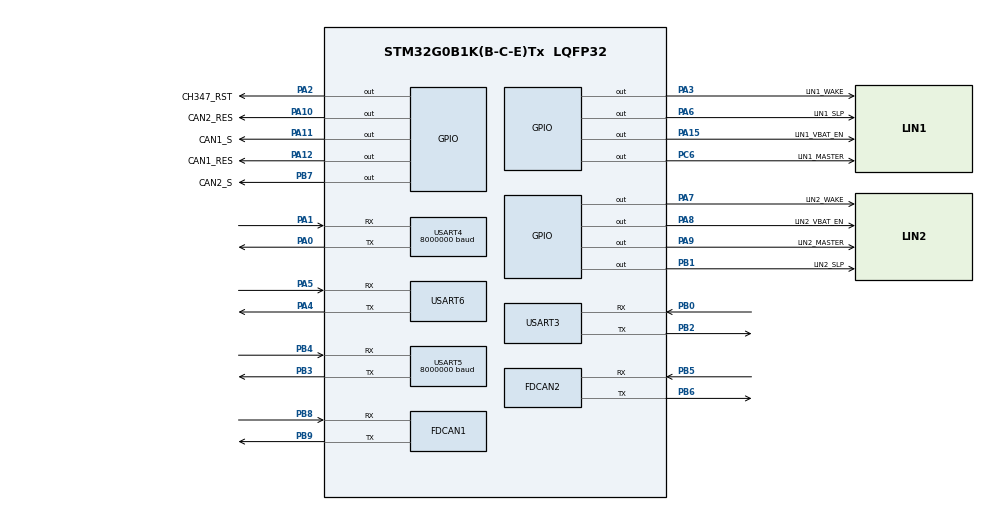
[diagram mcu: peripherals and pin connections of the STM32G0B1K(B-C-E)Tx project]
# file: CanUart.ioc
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Dma.Request0=USART4_RX
Dma.Request1=USART4_TX
Dma.Request2=USART5_RX
Dma.Request3=USART5_TX
Dma.USART4_RX.0.Direction=DMA_PERIPH_TO_MEMORY
Dma.USART4_RX.0.EventEnable=DISABLE
Dma.USART4_RX.0.Instance=DMA1_Channel2
Dma.USART4_RX.0.MemDataAlignment=DMA_MDATAALIGN_BYTE
Dma.USART4_RX.0.MemInc=DMA_MINC_ENABLE
Dma.USART4_RX.0.Mode=DMA_NORMAL
Dma.USART4_RX.0.PeriphDataAlignment=DMA_PDATAALIGN_BYTE
Dma.USART4_RX.0.PeriphInc=DMA_PINC_DISABLE
Dma.USART4_RX.0.Polarity=HAL_DMAMUX_REQ_GEN_RISING
Dma.USART4_RX.0.Priority=DMA_PRIORITY_LOW
Dma.USART4_RX.0.RequestNumber=1
Dma.USART4_RX.0.SignalID=NONE
Dma.USART4_RX.0.SyncEnable=DISABLE
Dma.USART4_RX.0.SyncPolarity=HAL_DMAMUX_SYNC_NO_EVENT
Dma.USART4_RX.0.SyncRequestNumber=1
Dma.USART4_RX.0.SyncSignalID=NONE
Dma.USART4_TX.1.Direction=DMA_MEMORY_TO_PERIPH
Dma.USART4_TX.1.EventEnable=DISABLE
Dma.USART4_TX.1.Instance=DMA1_Channel1
Dma.USART4_TX.1.MemDataAlignment=DMA_MDATAALIGN_BYTE
Dma.USART4_TX.1.MemInc=DMA_MINC_ENABLE
Dma.USART4_TX.1.Mode=DMA_NORMAL
Dma.USART4_TX.1.PeriphDataAlignment=DMA_PDATAALIGN_BYTE
Dma.USART4_TX.1.PeriphInc=DMA_PINC_DISABLE
Dma.USART4_TX.1.Polarity=HAL_DMAMUX_REQ_GEN_RISING
Dma.USART4_TX.1.Priority=DMA_PRIORITY_LOW
Dma.USART4_TX.1.RequestNumber=1
Dma.USART4_TX.1.SignalID=NONE
Dma.USART4_TX.1.SyncEnable=DISABLE
Dma.USART4_TX.1.SyncPolarity=HAL_DMAMUX_SYNC_NO_EVENT
Dma.USART4_TX.1.SyncRequestNumber=1
Dma.USART4_TX.1.SyncSignalID=NONE
Dma.USART5_RX.2.Direction=DMA_PERIPH_TO_MEMORY
Dma.USART5_RX.2.EventEnable=DISABLE
Dma.USART5_RX.2.Instance=DMA1_Channel3
Dma.USART5_RX.2.MemDataAlignment=DMA_MDATAALIGN_BYTE
Dma.USART5_RX.2.MemInc=DMA_MINC_ENABLE
Dma.USART5_RX.2.Mode=DMA_NORMAL
Dma.USART5_RX.2.PeriphDataAlignment=DMA_PDATAALIGN_BYTE
Dma.USART5_RX.2.PeriphInc=DMA_PINC_DISABLE
Dma.USART5_RX.2.Polarity=HAL_DMAMUX_REQ_GEN_RISING
Dma.USART5_RX.2.Priority=DMA_PRIORITY_LOW
Dma.USART5_RX.2.RequestNumber=1
Dma.USART5_RX.2.SignalID=NONE
Dma.USART5_RX.2.SyncEnable=DISABLE
Dma.USART5_RX.2.SyncPolarity=HAL_DMAMUX_SYNC_NO_EVENT
Dma.USART5_RX.2.SyncRequestNumber=1
Dma.USART5_RX.2.SyncSignalID=NONE
Dma.USART5_TX.3.Direction=DMA_MEMORY_TO_PERIPH
Dma.USART5_TX.3.EventEnable=DISABLE
Dma.USART5_TX.3.Instance=DMA1_Channel4
Dma.USART5_TX.3.MemDataAlignment=DMA_MDATAALIGN_BYTE
Dma.USART5_TX.3.MemInc=DMA_MINC_ENABLE
Dma.USART5_TX.3.Mode=DMA_NORMAL
Dma.USART5_TX.3.PeriphDataAlignment=DMA_PDATAALIGN_BYTE
Dma.USART5_TX.3.PeriphInc=DMA_PINC_DISABLE
Dma.USART5_TX.3.Polarity=HAL_DMAMUX_REQ_GEN_RISING
Dma.USART5_TX.3.Priority=DMA_PRIORITY_LOW
Dma.USART5_TX.3.RequestNumber=1
Dma.USART5_TX.3.SignalID=NONE
Dma.USART5_TX.3.SyncEnable=DISABLE
Dma.USART5_TX.3.SyncPolarity=HAL_DMAMUX_SYNC_NO_EVENT
Dma.USART5_TX.3.SyncRequestNumber=1
Dma.USART5_TX.3.SyncSignalID=NONE
FDCAN1.CalculateBaudRateNominal=1000000
FDCAN1.CalculateTimeBitNominal=1000
FDCAN1.CalculateTimeQuantumNominal=125.0
FDCAN1.DataPrescaler=2
FDCAN1.DataTimeSeg1=6
FDCAN1.FrameFormat=FDCAN_FRAME_FD_BRS
FDCAN1.NominalPrescaler=8
FDCAN1.NominalTimeSeg1=5
FDCAN2.CalculateBaudRateNominal=1000000
FDCAN2.CalculateTimeBitNominal=1000
FDCAN2.CalculateTimeQuantumNominal=125.0
FDCAN2.DataPrescaler=2
FDCAN2.DataTimeSeg1=6
FDCAN2.FrameFormat=FDCAN_FRAME_FD_BRS
FDCAN2.NominalPrescaler=8
FDCAN2.NominalTimeSeg1=5
Mcu.Family=STM32G0
Mcu.Name=STM32G0B1K(B-C-E)Tx
Mcu.Package=LQFP32
NVIC.DMA1_Ch4_7_DMA2_Ch1_5_DMAMUX1_OVR_IRQn=true\:0\:0\:false\:false\:true\:false\:true\:true
NVIC.DMA1_Channel1_IRQn=true\:0\:0\:false\:false\:true\:false\:true\:true
NVIC.DMA1_Channel2_3_IRQn=true\:0\:0\:false\:false\:true\:false\:true\:true
NVIC.TIM16_FDCAN_IT0_IRQn=true\:0\:0\:false\:false\:true\:true\:true\:true
NVIC.TIM17_FDCAN_IT1_IRQn=true\:0\:0\:false\:false\:true\:true\:true\:true
NVIC.USART3_4_5_6_LPUART1_IRQn=true\:0\:0\:false\:false\:true\:true\:true\:true
PA0.GPIO_Speed=GPIO_SPEED_FREQ_VERY_HIGH
PA0.Mode=Asynchronous
PA0.Signal=USART4_TX
PA1.GPIO_Speed=GPIO_SPEED_FREQ_VERY_HIGH
PA1.Mode=Asynchronous
PA1.Signal=USART4_RX
PA10.GPIO_Label=CAN2_RES
PA10.Signal=GPIO_Output
PA11\ [PA9].GPIO_Label=CAN1_S
PA11\ [PA9].Signal=GPIO_Output
PA12\ [PA10].GPIO_Label=CAN1_RES
PA12\ [PA10].Signal=GPIO_Output
PA13.Mode=Serial_Wire
PA13.Signal=SYS_SWDIO
PA14-BOOT0.Mode=Serial_Wire
PA14-BOOT0.Signal=SYS_SWCLK
PA15.GPIO_Label=LIN1_VBAT_EN
PA15.Signal=GPIO_Output
PA2.GPIO_Label=CH347_RST
PA2.Signal=GPIO_Output
PA3.GPIO_Label=LIN1_WAKE
PA3.Signal=GPIO_Output
PA4.GPIO_Speed=GPIO_SPEED_FREQ_VERY_HIGH
PA4.Mode=Asynchronous
PA4.Signal=USART6_TX
PA5.GPIO_Speed=GPIO_SPEED_FREQ_VERY_HIGH
PA5.Mode=Asynchronous
PA5.Signal=USART6_RX
PA6.GPIO_Label=LIN1_SLP
PA6.Signal=GPIO_Output
PA7.GPIO_Label=LIN2_WAKE
PA7.Signal=GPIO_Output
PA8.GPIO_Label=LIN2_VBAT_EN
PA8.Signal=GPIO_Output
PA9.GPIO_Label=LIN2_MASTER
PA9.Signal=GPIO_Output
PB0.GPIO_Speed=GPIO_SPEED_FREQ_VERY_HIGH
PB0.Mode=LIN
PB0.Signal=USART3_RX
PB1.GPIO_Label=LIN2_SLP
PB1.Signal=GPIO_Output
PB2.GPIO_Speed=GPIO_SPEED_FREQ_VERY_HIGH
PB2.Mode=LIN
PB2.Signal=USART3_TX
PB3.GPIO_Speed=GPIO_SPEED_FREQ_VERY_HIGH
PB3.Mode=Asynchronous
PB3.Signal=USART5_TX
PB4.GPIO_Speed=GPIO_SPEED_FREQ_VERY_HIGH
PB4.Mode=Asynchronous
PB4.Signal=USART5_RX
PB5.GPIO_Speed=GPIO_SPEED_FREQ_VERY_HIGH
PB5.Mode=FDCAN_Activate
PB5.Signal=FDCAN2_RX
PB6.GPIO_Speed=GPIO_SPEED_FREQ_VERY_HIGH
PB6.Mode=FDCAN_Activate
PB6.Signal=FDCAN2_TX
PB7.GPIO_Label=CAN2_S
PB7.Signal=GPIO_Output
PB8.GPIO_Speed=GPIO_SPEED_FREQ_VERY_HIGH
PB8.Mode=FDCAN_Activate
PB8.Signal=FDCAN1_RX
PB9.GPIO_Speed=GPIO_SPEED_FREQ_VERY_HIGH
PB9.Mode=FDCAN_Activate
PB9.Signal=FDCAN1_TX
PC14-OSC32_IN\ (PC14).Mode=HSE-External-Clock-Source
PC14-OSC32_IN\ (PC14).Signal=RCC_OSC_IN
PC15-OSC32_OUT\ (PC15).Mode=OSC enable
PC15-OSC32_OUT\ (PC15).Signal=RCC_OSC_EN
PC6.GPIO_Label=LIN1_MASTER
PC6.Signal=GPIO_Output
ProjectManager.HeapSize=0x200
ProjectManager.StackSize=0x400
ProjectManager.TargetToolchain=Makefile
RCC.ADCFreq_Value=64000000
RCC.AHBFreq_Value=64000000
RCC.CortexFreq_Value=64000000
RCC.EXTERNAL_CLOCK_VALUE=48000
RCC.HCLKFreq_Value=64000000
RCC.HSE_VALUE=8000000
RCC.HSI48_VALUE=48000000
RCC.HSI_VALUE=16000000
RCC.LSE_VALUE=32768
RCC.PLLN=16
RCC.PLLSourceVirtual=RCC_PLLSOURCE_HSE
RCC.SYSCLKFreq_VALUE=64000000
RCC.SYSCLKSource=RCC_SYSCLKSOURCE_PLLCLK
RCC.USBFreq_Value=48000000
RCC.VCOOutputFreq_Value=128000000
USART3.VirtualMode-LIN=VM_LIN
USART4.BaudRate=8000000
USART4.OverSampling=UART_OVERSAMPLING_8
USART4.VirtualMode-Asynchronous=VM_ASYNC
USART5.BaudRate=8000000
USART5.OverSampling=UART_OVERSAMPLING_8
USART5.VirtualMode-Asynchronous=VM_ASYNC
USART6.VirtualMode-Asynchronous=VM_ASYNC
VP_SYS_VS_DBSignals.Mode=DisableDeadBatterySignals
board=custom

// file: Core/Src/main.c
/* USER CODE BEGIN Header */
/**
  ******************************************************************************
  * @file           : main.c
  * @brief          : Main program body
  ******************************************************************************
  * @attention
  *
  * Copyright (c) 2026 STMicroelectronics.
  * All rights reserved.
  *
  * This software is licensed under terms that can be found in the LICENSE file
  * in the root directory of this software component.
  * If no LICENSE file comes with this software, it is provided AS-IS.
  *
  ******************************************************************************
  */
/* USER CODE END Header */
#include "main.h"

FDCAN_HandleTypeDef hfdcan1;
FDCAN_HandleTypeDef hfdcan2;

UART_HandleTypeDef huart3;
UART_HandleTypeDef huart4;
UART_HandleTypeDef huart5;
UART_HandleTypeDef huart6;
DMA_HandleTypeDef hdma_usart4_rx;
DMA_HandleTypeDef hdma_usart4_tx;
DMA_HandleTypeDef hdma_usart5_rx;
DMA_HandleTypeDef hdma_usart5_tx;

void SystemClock_Config(void);
static void MX_GPIO_Init(void);
static void MX_DMA_Init(void);
static void MX_FDCAN1_Init(void);
static void MX_FDCAN2_Init(void);
static void MX_USART3_UART_Init(void);
static void MX_USART4_UART_Init(void);
static void MX_USART5_UART_Init(void);
static void MX_USART6_UART_Init(void);

/* USER CODE BEGIN 0 */
#define BUFFER_SIZE (72*2*100)//canfd最长数据段64字节，帧头8字节，共72字节，留两帧空间

uint8_t uart4RxData[BUFFER_SIZE];
uint8_t uart5RxData[BUFFER_SIZE];

/* USER CODE END 0 */

int main(void)
{
  /* USER CODE BEGIN 1 */

  // SEGGER_RTT_ConfigUpBuffer(0, NULL, NULL, 0, SEGGER_RTT_MODE_BLOCK_IF_FIFO_FULL);

  /* USER CODE END 1 */

  /* MCU Configuration--------------------------------------------------------*/

  /* Reset of all peripherals, Initializes the Flash interface and the Systick. */
  HAL_Init();

  /* Configure the system clock */
  SystemClock_Config();

  /* Initialize all configured peripherals */
  MX_GPIO_Init();
  MX_DMA_Init();
  MX_FDCAN1_Init();
  MX_FDCAN2_Init();
  MX_USART3_UART_Init();
  MX_USART4_UART_Init();
  MX_USART5_UART_Init();
  MX_USART6_UART_Init();
  /* USER CODE BEGIN 2 */

  //复位CH347
  HAL_Delay(1000);
  HAL_GPIO_WritePin(CH347_RST_GPIO_Port, CH347_RST_Pin, GPIO_PIN_SET);
  HAL_Delay(1000);

  __HAL_UART_DISABLE(&huart4);
  HAL_UARTEx_ReceiveToIdle_DMA(&huart4, uart4RxData, BUFFER_SIZE);
  __HAL_UART_ENABLE(&huart4);

  __HAL_UART_DISABLE(&huart5);
  HAL_UARTEx_ReceiveToIdle_DMA(&huart5, uart5RxData, BUFFER_SIZE);
  __HAL_UART_ENABLE(&huart5);

  /* USER CODE END 2 */

  /* Infinite loop */
  while (1)
  {

  }
}

void SystemClock_Config(void)
{
  RCC_OscInitTypeDef RCC_OscInitStruct = {0};
  RCC_ClkInitTypeDef RCC_ClkInitStruct = {0};

  /** Configure the main internal regulator output voltage
  */
  HAL_PWREx_ControlVoltageScaling(PWR_REGULATOR_VOLTAGE_SCALE1);

  /** Initializes the RCC Oscillators according to the specified parameters
  * in the RCC_OscInitTypeDef structure.
  */
  RCC_OscInitStruct.OscillatorType = RCC_OSCILLATORTYPE_HSE;
  RCC_OscInitStruct.HSEState = RCC_HSE_BYPASS;
  RCC_OscInitStruct.PLL.PLLState = RCC_PLL_ON;
  RCC_OscInitStruct.PLL.PLLSource = RCC_PLLSOURCE_HSE;
  RCC_OscInitStruct.PLL.PLLM = RCC_PLLM_DIV1;
  RCC_OscInitStruct.PLL.PLLN = 18;
  RCC_OscInitStruct.PLL.PLLP = RCC_PLLP_DIV2;
  RCC_OscInitStruct.PLL.PLLQ = RCC_PLLQ_DIV2;
  RCC_OscInitStruct.PLL.PLLR = RCC_PLLR_DIV2;
  if (HAL_RCC_OscConfig(&RCC_OscInitStruct) != HAL_OK)
  {
    Error_Handler();
  }

  /** Initializes the CPU, AHB and APB buses clocks
  */
  RCC_ClkInitStruct.ClockType = RCC_CLOCKTYPE_HCLK|RCC_CLOCKTYPE_SYSCLK
                              |RCC_CLOCKTYPE_PCLK1;
  RCC_ClkInitStruct.SYSCLKSource = RCC_SYSCLKSOURCE_PLLCLK;
  RCC_ClkInitStruct.AHBCLKDivider = RCC_SYSCLK_DIV1;
  RCC_ClkInitStruct.APB1CLKDivider = RCC_HCLK_DIV1;

  if (HAL_RCC_ClockConfig(&RCC_ClkInitStruct, FLASH_LATENCY_2) != HAL_OK)
  {
    Error_Handler();
  }
}

static void MX_FDCAN1_Init(void)
{

  hfdcan1.Instance = FDCAN1;
  hfdcan1.Init.ClockDivider = FDCAN_CLOCK_DIV1;
  hfdcan1.Init.FrameFormat = FDCAN_FRAME_FD_BRS;
  hfdcan1.Init.Mode = FDCAN_MODE_NORMAL;
  hfdcan1.Init.AutoRetransmission = DISABLE;
  hfdcan1.Init.TransmitPause = DISABLE;
  hfdcan1.Init.ProtocolException = DISABLE;
  hfdcan1.Init.NominalPrescaler = 1;
  hfdcan1.Init.NominalSyncJumpWidth = 1;
  hfdcan1.Init.NominalTimeSeg1 = 53;
  hfdcan1.Init.NominalTimeSeg2 = 18;
  hfdcan1.Init.DataPrescaler = 1;
  hfdcan1.Init.DataSyncJumpWidth = 1;
  hfdcan1.Init.DataTimeSeg1 = 12;
  hfdcan1.Init.DataTimeSeg2 = 5;
  hfdcan1.Init.StdFiltersNbr = 0;
  hfdcan1.Init.ExtFiltersNbr = 0;
  hfdcan1.Init.TxFifoQueueMode = FDCAN_TX_FIFO_OPERATION;
  if (HAL_FDCAN_Init(&hfdcan1) != HAL_OK)
  {
    Error_Handler();
  }
  /* USER CODE BEGIN FDCAN1_Init 2 */

  //控制fdcan1的
  HAL_GPIO_WritePin(CAN2_S_GPIO_Port, CAN2_S_Pin, GPIO_PIN_RESET);
  HAL_GPIO_WritePin(CAN2_RES_GPIO_Port, CAN2_RES_Pin, GPIO_PIN_SET);

  HAL_FDCAN_ConfigGlobalFilter(&hfdcan1, FDCAN_ACCEPT_IN_RX_FIFO0, FDCAN_ACCEPT_IN_RX_FIFO1, FDCAN_FILTER_REMOTE, FDCAN_FILTER_REMOTE);

  HAL_FDCAN_ConfigInterruptLines(&hfdcan1,FDCAN_IT_GROUP_RX_FIFO0,FDCAN_INTERRUPT_LINE0);
  HAL_FDCAN_ConfigInterruptLines(&hfdcan1,FDCAN_IT_GROUP_RX_FIFO1,FDCAN_INTERRUPT_LINE1);

  HAL_FDCAN_ActivateNotification(&hfdcan1, FDCAN_IT_RX_FIFO0_NEW_MESSAGE,0);
  HAL_FDCAN_ActivateNotification(&hfdcan1, FDCAN_IT_RX_FIFO1_NEW_MESSAGE,0);
  HAL_FDCAN_ActivateNotification(&hfdcan1, FDCAN_IT_TX_COMPLETE,FDCAN_TX_BUFFER0|FDCAN_TX_BUFFER1|FDCAN_TX_BUFFER2);

  if (HAL_FDCAN_ConfigTxDelayCompensation(&hfdcan1, 8, 4) != HAL_OK)
  {
      Error_Handler();
  }

  if (HAL_FDCAN_EnableTxDelayCompensation(&hfdcan1) != HAL_OK)
  {
      Error_Handler();
  }

  HAL_FDCAN_Start(&hfdcan1);

  /* USER CODE END FDCAN1_Init 2 */

}

static void MX_FDCAN2_Init(void)
{

  hfdcan2.Instance = FDCAN2;
  hfdcan2.Init.ClockDivider = FDCAN_CLOCK_DIV1;
  hfdcan2.Init.FrameFormat = FDCAN_FRAME_FD_BRS;
  hfdcan2.Init.Mode = FDCAN_MODE_NORMAL;
  hfdcan2.Init.AutoRetransmission = DISABLE;
  hfdcan2.Init.TransmitPause = DISABLE;
  hfdcan2.Init.ProtocolException = DISABLE;
  hfdcan2.Init.NominalPrescaler = 1;
  hfdcan2.Init.NominalSyncJumpWidth = 1;
  hfdcan2.Init.NominalTimeSeg1 = 53;
  hfdcan2.Init.NominalTimeSeg2 = 18;
  hfdcan2.Init.DataPrescaler = 1;
  hfdcan2.Init.DataSyncJumpWidth = 1;
  hfdcan2.Init.DataTimeSeg1 = 12;
  hfdcan2.Init.DataTimeSeg2 = 5;
  hfdcan2.Init.StdFiltersNbr = 0;
  hfdcan2.Init.ExtFiltersNbr = 0;
  hfdcan2.Init.TxFifoQueueMode = FDCAN_TX_FIFO_OPERATION;
  if (HAL_FDCAN_Init(&hfdcan2) != HAL_OK)
  {
    Error_Handler();
  }
  /* USER CODE BEGIN FDCAN2_Init 2 */

  //控制fdcan2的
  HAL_GPIO_WritePin(CAN1_S_GPIO_Port, CAN1_S_Pin, GPIO_PIN_RESET);
  HAL_GPIO_WritePin(CAN1_RES_GPIO_Port, CAN1_RES_Pin, GPIO_PIN_SET);

  HAL_FDCAN_ConfigGlobalFilter(&hfdcan2, FDCAN_ACCEPT_IN_RX_FIFO0, FDCAN_ACCEPT_IN_RX_FIFO0, FDCAN_FILTER_REMOTE, FDCAN_FILTER_REMOTE);

  HAL_FDCAN_ConfigInterruptLines(&hfdcan2,FDCAN_IT_GROUP_RX_FIFO0,FDCAN_INTERRUPT_LINE1);
  HAL_FDCAN_ConfigInterruptLines(&hfdcan2,FDCAN_IT_GROUP_RX_FIFO1,FDCAN_INTERRUPT_LINE0);

  HAL_FDCAN_ActivateNotification(&hfdcan2, FDCAN_IT_RX_FIFO0_NEW_MESSAGE,0);
  HAL_FDCAN_ActivateNotification(&hfdcan2, FDCAN_IT_RX_FIFO1_NEW_MESSAGE,0);
  HAL_FDCAN_ActivateNotification(&hfdcan2, FDCAN_IT_TX_COMPLETE,FDCAN_TX_BUFFER0|FDCAN_TX_BUFFER1|FDCAN_TX_BUFFER2);

  if (HAL_FDCAN_ConfigTxDelayCompensation(&hfdcan2, 8, 4) != HAL_OK)
  {
      Error_Handler();
  }

  if (HAL_FDCAN_EnableTxDelayCompensation(&hfdcan2) != HAL_OK)
  {
      Error_Handler();
  }

  HAL_FDCAN_Start(&hfdcan2);

  /* USER CODE END FDCAN2_Init 2 */

}

static void MX_USART3_UART_Init(void)
{

  huart3.Instance = USART3;
  huart3.Init.BaudRate = 115200;
  huart3.Init.WordLength = UART_WORDLENGTH_8B;
  huart3.Init.StopBits = UART_STOPBITS_1;
  huart3.Init.Parity = UART_PARITY_NONE;
  huart3.Init.Mode = UART_MODE_TX_RX;
  huart3.Init.HwFlowCtl = UART_HWCONTROL_NONE;
  huart3.Init.OverSampling = UART_OVERSAMPLING_16;
  huart3.Init.OneBitSampling = UART_ONE_BIT_SAMPLE_DISABLE;
  huart3.Init.ClockPrescaler = UART_PRESCALER_DIV1;
  huart3.AdvancedInit.AdvFeatureInit = UART_ADVFEATURE_NO_INIT;
  if (HAL_LIN_Init(&huart3, UART_LINBREAKDETECTLENGTH_10B) != HAL_OK)
  {
    Error_Handler();
  }
  if (HAL_UARTEx_SetTxFifoThreshold(&huart3, UART_TXFIFO_THRESHOLD_1_8) != HAL_OK)
  {
    Error_Handler();
  }
  if (HAL_UARTEx_SetRxFifoThreshold(&huart3, UART_RXFIFO_THRESHOLD_1_8) != HAL_OK)
  {
    Error_Handler();
  }
  if (HAL_UARTEx_DisableFifoMode(&huart3) != HAL_OK)
  {
    Error_Handler();
  }

}

static void MX_USART4_UART_Init(void)
{

  huart4.Instance = USART4;
  huart4.Init.BaudRate = 9000000;
  huart4.Init.WordLength = UART_WORDLENGTH_8B;
  huart4.Init.StopBits = UART_STOPBITS_1;
  huart4.Init.Parity = UART_PARITY_NONE;
  huart4.Init.Mode = UART_MODE_TX_RX;
  huart4.Init.HwFlowCtl = UART_HWCONTROL_NONE;
  huart4.Init.OverSampling = UART_OVERSAMPLING_8;
  huart4.Init.OneBitSampling = UART_ONE_BIT_SAMPLE_DISABLE;
  huart4.Init.ClockPrescaler = UART_PRESCALER_DIV1;
  huart4.AdvancedInit.AdvFeatureInit = UART_ADVFEATURE_NO_INIT;
  if (HAL_UART_Init(&huart4) != HAL_OK)
  {
    Error_Handler();
  }

}

static void MX_USART5_UART_Init(void)
{

  huart5.Instance = USART5;
  huart5.Init.BaudRate = 9000000;
  huart5.Init.WordLength = UART_WORDLENGTH_8B;
  huart5.Init.StopBits = UART_STOPBITS_1;
  huart5.Init.Parity = UART_PARITY_NONE;
  huart5.Init.Mode = UART_MODE_TX_RX;
  huart5.Init.HwFlowCtl = UART_HWCONTROL_NONE;
  huart5.Init.OverSampling = UART_OVERSAMPLING_8;
  huart5.Init.OneBitSampling = UART_ONE_BIT_SAMPLE_DISABLE;
  huart5.Init.ClockPrescaler = UART_PRESCALER_DIV1;
  huart5.AdvancedInit.AdvFeatureInit = UART_ADVFEATURE_NO_INIT;
  if (HAL_UART_Init(&huart5) != HAL_OK)
  {
    Error_Handler();
  }

}

static void MX_USART6_UART_Init(void)
{

  huart6.Instance = USART6;
  huart6.Init.BaudRate = 115200;
  huart6.Init.WordLength = UART_WORDLENGTH_8B;
  huart6.Init.StopBits = UART_STOPBITS_1;
  huart6.Init.Parity = UART_PARITY_NONE;
  huart6.Init.Mode = UART_MODE_TX_RX;
  huart6.Init.HwFlowCtl = UART_HWCONTROL_NONE;
  huart6.Init.OverSampling = UART_OVERSAMPLING_16;
  huart6.Init.OneBitSampling = UART_ONE_BIT_SAMPLE_DISABLE;
  huart6.Init.ClockPrescaler = UART_PRESCALER_DIV1;
  huart6.AdvancedInit.AdvFeatureInit = UART_ADVFEATURE_NO_INIT;
  if (HAL_UART_Init(&huart6) != HAL_OK)
  {
    Error_Handler();
  }

}

static void MX_DMA_Init(void)
{

  /* DMA controller clock enable */
  __HAL_RCC_DMA1_CLK_ENABLE();

  /* DMA interrupt init */
  /* DMA1_Channel1_IRQn interrupt configuration */
  HAL_NVIC_SetPriority(DMA1_Channel1_IRQn, 0, 0);
  HAL_NVIC_EnableIRQ(DMA1_Channel1_IRQn);
  /* DMA1_Channel2_3_IRQn interrupt configuration */
  HAL_NVIC_SetPriority(DMA1_Channel2_3_IRQn, 0, 0);
  HAL_NVIC_EnableIRQ(DMA1_Channel2_3_IRQn);
  /* DMA1_Ch4_7_DMA2_Ch1_5_DMAMUX1_OVR_IRQn interrupt configuration */
  HAL_NVIC_SetPriority(DMA1_Ch4_7_DMA2_Ch1_5_DMAMUX1_OVR_IRQn, 0, 0);
  HAL_NVIC_EnableIRQ(DMA1_Ch4_7_DMA2_Ch1_5_DMAMUX1_OVR_IRQn);

}

static void MX_GPIO_Init(void)
{
  GPIO_InitTypeDef GPIO_InitStruct = {0};

  /* GPIO Ports Clock Enable */
  __HAL_RCC_GPIOB_CLK_ENABLE();
  __HAL_RCC_GPIOC_CLK_ENABLE();
  __HAL_RCC_GPIOA_CLK_ENABLE();

  /*Configure GPIO pin Output Level */
  HAL_GPIO_WritePin(CH347_RST_GPIO_Port, CH347_RST_Pin, GPIO_PIN_SET);
  HAL_GPIO_WritePin(GPIOA, LIN1_WAKE_Pin|LIN1_SLP_Pin|LIN2_WAKE_Pin
                          |LIN2_VBAT_EN_Pin|LIN2_MASTER_Pin|CAN2_RES_Pin|CAN1_S_Pin
                          |CAN1_RES_Pin|LIN1_VBAT_EN_Pin, GPIO_PIN_RESET);

  /*Configure GPIO pin Output Level */
  HAL_GPIO_WritePin(GPIOB, LIN2_SLP_Pin|CAN2_S_Pin, GPIO_PIN_RESET);

  /*Configure GPIO pin Output Level */
  HAL_GPIO_WritePin(LIN1_MASTER_GPIO_Port, LIN1_MASTER_Pin, GPIO_PIN_RESET);

  /*Configure GPIO pin : PC15 */
  GPIO_InitStruct.Pin = GPIO_PIN_15;
  GPIO_InitStruct.Mode = GPIO_MODE_AF_PP;
  GPIO_InitStruct.Pull = GPIO_NOPULL;
  GPIO_InitStruct.Speed = GPIO_SPEED_FREQ_LOW;
  GPIO_InitStruct.Alternate = GPIO_AF1_OSC;
  HAL_GPIO_Init(GPIOC, &GPIO_InitStruct);

  /*Configure GPIO pins : CH347_RST_Pin LIN1_WAKE_Pin LIN1_SLP_Pin LIN2_WAKE_Pin
                           LIN2_VBAT_EN_Pin LIN2_MASTER_Pin CAN2_RES_Pin CAN1_S_Pin
                           CAN1_RES_Pin LIN1_VBAT_EN_Pin */
  GPIO_InitStruct.Pin = CH347_RST_Pin|LIN1_WAKE_Pin|LIN1_SLP_Pin|LIN2_WAKE_Pin
                          |LIN2_VBAT_EN_Pin|LIN2_MASTER_Pin|CAN2_RES_Pin|CAN1_S_Pin
                          |CAN1_RES_Pin|LIN1_VBAT_EN_Pin;
  GPIO_InitStruct.Mode = GPIO_MODE_OUTPUT_PP;
  GPIO_InitStruct.Pull = GPIO_NOPULL;
  GPIO_InitStruct.Speed = GPIO_SPEED_FREQ_LOW;
  HAL_GPIO_Init(GPIOA, &GPIO_InitStruct);

  /*Configure GPIO pins : LIN2_SLP_Pin CAN2_S_Pin */
  GPIO_InitStruct.Pin = LIN2_SLP_Pin|CAN2_S_Pin;
  GPIO_InitStruct.Mode = GPIO_MODE_OUTPUT_PP;
  GPIO_InitStruct.Pull = GPIO_NOPULL;
  GPIO_InitStruct.Speed = GPIO_SPEED_FREQ_LOW;
  HAL_GPIO_Init(GPIOB, &GPIO_InitStruct);

  /*Configure GPIO pin : LIN1_MASTER_Pin */
  GPIO_InitStruct.Pin = LIN1_MASTER_Pin;
  GPIO_InitStruct.Mode = GPIO_MODE_OUTPUT_PP;
  GPIO_InitStruct.Pull = GPIO_NOPULL;
  GPIO_InitStruct.Speed = GPIO_SPEED_FREQ_LOW;
  HAL_GPIO_Init(LIN1_MASTER_GPIO_Port, &GPIO_InitStruct);

}

/* USER CODE BEGIN 4 */

#define FDCAN_ELEMENT_MASK_STDID ((uint32_t)0x1FFC0000U) /* Standard Identifier         */
#define FDCAN_ELEMENT_MASK_EXTID ((uint32_t)0x1FFFFFFFU) /* Extended Identifier         */
#define FDCAN_ELEMENT_MASK_RTR   ((uint32_t)0x20000000U) /* Remote Transmission Request */
#define FDCAN_ELEMENT_MASK_XTD   ((uint32_t)0x40000000U) /* Extended Identifier         */
#define FDCAN_ELEMENT_MASK_ESI   ((uint32_t)0x80000000U) /* Error State Indicator       */
#define FDCAN_ELEMENT_MASK_TS    ((uint32_t)0x0000FFFFU) /* Timestamp                   */
#define FDCAN_ELEMENT_MASK_DLC   ((uint32_t)0x000F0000U) /* Data Length Code            */
#define FDCAN_ELEMENT_MASK_BRS   ((uint32_t)0x00100000U) /* Bit Rate Switch             */
#define FDCAN_ELEMENT_MASK_FDF   ((uint32_t)0x00200000U) /* FD Format                   */
#define FDCAN_ELEMENT_MASK_EFC   ((uint32_t)0x00800000U) /* Event FIFO Control          */
#define FDCAN_ELEMENT_MASK_MM    ((uint32_t)0xFF000000U) /* Message Marker              */
#define FDCAN_ELEMENT_MASK_FIDX  ((uint32_t)0x7F000000U) /* Filter Index                */
#define FDCAN_ELEMENT_MASK_ANMF  ((uint32_t)0x80000000U) /* Accepted Non-matching Frame */
#define FDCAN_ELEMENT_MASK_ET    ((uint32_t)0x00C00000U) /* Event type                  */

#define SRAMCAN_FLS_NBR                  (28U)         /* Max. Filter List Standard Number      */
#define SRAMCAN_FLE_NBR                  ( 8U)         /* Max. Filter List Extended Number      */
#define SRAMCAN_RF0_NBR                  ( 3U)         /* RX FIFO 0 Elements Number             */
#define SRAMCAN_RF1_NBR                  ( 3U)         /* RX FIFO 1 Elements Number             */
#define SRAMCAN_TEF_NBR                  ( 3U)         /* TX Event FIFO Elements Number         */
#define SRAMCAN_TFQ_NBR                  ( 3U)         /* TX FIFO/Queue Elements Number         */

#define SRAMCAN_FLS_SIZE            ( 1U * 4U)         /* Filter Standard Element Size in bytes */
#define SRAMCAN_FLE_SIZE            ( 2U * 4U)         /* Filter Extended Element Size in bytes */
#define SRAMCAN_RF0_SIZE            (18U * 4U)         /* RX FIFO 0 Elements Size in bytes      */
#define SRAMCAN_RF1_SIZE            (18U * 4U)         /* RX FIFO 1 Elements Size in bytes      */
#define SRAMCAN_TEF_SIZE            ( 2U * 4U)         /* TX Event FIFO Elements Size in bytes  */
#define SRAMCAN_TFQ_SIZE            (18U * 4U)         /* TX FIFO/Queue Elements Size in bytes  */

#define SRAMCAN_FLSSA ((uint32_t)0)                                                      /* Filter List Standard Start
                                                                                            Address                  */
#define SRAMCAN_FLESA ((uint32_t)(SRAMCAN_FLSSA + (SRAMCAN_FLS_NBR * SRAMCAN_FLS_SIZE))) /* Filter List Extended Start
                                                                                            Address                  */
#define SRAMCAN_RF0SA ((uint32_t)(SRAMCAN_FLESA + (SRAMCAN_FLE_NBR * SRAMCAN_FLE_SIZE))) /* Rx FIFO 0 Start Address  */
#define SRAMCAN_RF1SA ((uint32_t)(SRAMCAN_RF0SA + (SRAMCAN_RF0_NBR * SRAMCAN_RF0_SIZE))) /* Rx FIFO 1 Start Address  */
#define SRAMCAN_TEFSA ((uint32_t)(SRAMCAN_RF1SA + (SRAMCAN_RF1_NBR * SRAMCAN_RF1_SIZE))) /* Tx Event FIFO Start
                                                                                            Address */
#define SRAMCAN_TFQSA ((uint32_t)(SRAMCAN_TEFSA + (SRAMCAN_TEF_NBR * SRAMCAN_TEF_SIZE))) /* Tx FIFO/Queue Start
                                                                                            Address                  */
#define SRAMCAN_SIZE  ((uint32_t)(SRAMCAN_TFQSA + (SRAMCAN_TFQ_NBR * SRAMCAN_TFQ_SIZE))) /* Message RAM size         */

static const uint8_t DLCtoBytes[] = {0, 1, 2, 3, 4, 5, 6, 7, 8, 12, 16, 20, 24, 32, 48, 64};

uint8_t g_shadow_tx_fifo_q[2][SRAMCAN_TFQ_NBR][SRAMCAN_TFQ_SIZE]; /* Tx FIFO/Queue shadow */

/**
  * @brief  Get an FDCAN frame from the Rx FIFO zone into the message RAM.
  * @param  hfdcan pointer to an FDCAN_HandleTypeDef structure that contains
  *         the configuration information for the specified FDCAN.
  * @param  RxLocation Location of the received message to be read.
  *         This parameter can be a value of @arg FDCAN_Rx_location.
  * @retval HAL status
  */
HAL_StatusTypeDef HAL_FDCAN_RxMessageDMA(FDCAN_HandleTypeDef *hfdcan, uint32_t RxLocation)
{
  uint32_t *RxAddress;
  uint8_t  *pData;
  uint32_t ByteCounter;
  uint32_t GetIndex;
  HAL_FDCAN_StateTypeDef state = hfdcan->State;

  /* Check function parameters */
  assert_param(IS_FDCAN_RX_FIFO(RxLocation));

  if (state == HAL_FDCAN_STATE_BUSY)
  {
    if (RxLocation == FDCAN_RX_FIFO0) /* Rx element is assigned to the Rx FIFO 0 */
    {
      /* Check that the Rx FIFO 0 is not empty */
      if ((hfdcan->Instance->RXF0S & FDCAN_RXF0S_F0FL) == 0U)
      {
        /* Update error code */
        hfdcan->ErrorCode |= HAL_FDCAN_ERROR_FIFO_EMPTY;

        return HAL_ERROR;
      }
      else
      {
        /* Calculate Rx FIFO 0 element index */
        GetIndex = ((hfdcan->Instance->RXF0S & FDCAN_RXF0S_F0GI) >> FDCAN_RXF0S_F0GI_Pos);

        /* Check that the Rx FIFO 0 is full & overwrite mode is on */
        if (((hfdcan->Instance->RXF0S & FDCAN_RXF0S_F0F) >> FDCAN_RXF0S_F0F_Pos) == 1U)
        {
          if (((hfdcan->Instance->RXGFC & FDCAN_RXGFC_F0OM) >> FDCAN_RXGFC_F0OM_Pos) == FDCAN_RX_FIFO_OVERWRITE)
          {
            /* When overwrite status is on discard first message in FIFO */
            /* GetIndex is incremented by one and wraps to 0 in case it overflows the FIFO size */
            GetIndex = (GetIndex + 1U) & SRAMCAN_RF0_NBR;
          }
        }

        /* Calculate Rx FIFO 0 element address */
        RxAddress = (uint32_t *)(hfdcan->msgRam.RxFIFO0SA + (GetIndex * SRAMCAN_RF0_SIZE));
      }
    }
    else /* Rx element is assigned to the Rx FIFO 1 */
    {
      /* Check that the Rx FIFO 1 is not empty */
      if ((hfdcan->Instance->RXF1S & FDCAN_RXF1S_F1FL) == 0U)
      {
        /* Update error code */
        hfdcan->ErrorCode |= HAL_FDCAN_ERROR_FIFO_EMPTY;

        return HAL_ERROR;
      }
      else
      {
        /* Calculate Rx FIFO 1 element index */
        GetIndex = ((hfdcan->Instance->RXF1S & FDCAN_RXF1S_F1GI) >> FDCAN_RXF1S_F1GI_Pos);

        /* Check that the Rx FIFO 1 is full & overwrite mode is on */
        if (((hfdcan->Instance->RXF1S & FDCAN_RXF1S_F1F) >> FDCAN_RXF1S_F1F_Pos) == 1U)
        {
          if (((hfdcan->Instance->RXGFC & FDCAN_RXGFC_F1OM) >> FDCAN_RXGFC_F1OM_Pos) == FDCAN_RX_FIFO_OVERWRITE)
          {
            /* When overwrite status is on discard first message in FIFO */
            /* GetIndex is incremented by one and wraps to 0 in case it overflows the FIFO size */
            GetIndex = (GetIndex + 1U) & SRAMCAN_RF1_NBR;
          }
        }

        /* Calculate Rx FIFO 1 element address */
        RxAddress = (uint32_t *)(hfdcan->msgRam.RxFIFO1SA + (GetIndex * SRAMCAN_RF1_SIZE));
      }
    }

    /* Retrieve DataLength */
    HAL_UART_Transmit(&huart4, (uint8_t *)RxAddress, 2*4+DLCtoBytes[((*(RxAddress+1) & FDCAN_ELEMENT_MASK_DLC) >> 16U)],1000);

    if (RxLocation == FDCAN_RX_FIFO0) /* Rx element is assigned to the Rx FIFO 0 */
    {
      /* Acknowledge the Rx FIFO 0 that the oldest element is read so that it increments the GetIndex */
      hfdcan->Instance->RXF0A = GetIndex;
    }
    else /* Rx element is assigned to the Rx FIFO 1 */
    {
      /* Acknowledge the Rx FIFO 1 that the oldest element is read so that it increments the GetIndex */
      hfdcan->Instance->RXF1A = GetIndex;
    }

    /* Return function status */
    return HAL_OK;
  }
  else
  {
    /* Update error code */
    hfdcan->ErrorCode |= HAL_FDCAN_ERROR_NOT_STARTED;

    return HAL_ERROR;
  }
}

/**
  * @brief  Add a message to the Tx FIFO/Queue and activate the corresponding transmission request
  * @param  hfdcan pointer to an FDCAN_HandleTypeDef structure that contains
  *         the configuration information for the specified FDCAN.
  * @param  pTxHeader pointer to a FDCAN_TxHeaderTypeDef structure.
  * @param  pTxData pointer to a buffer containing the payload of the Tx frame.
  * @retval HAL status
  */
HAL_StatusTypeDef HAL_FDCAN_AddMessageToTxFifoQ_Raw(FDCAN_HandleTypeDef *hfdcan, uint32_t can_frame_pos, uint8_t frame_len)
{
  uint32_t PutIndex;

  if (hfdcan->State == HAL_FDCAN_STATE_BUSY)
  {
    /* Check that the Tx FIFO/Queue is not full */
    if ((hfdcan->Instance->TXFQS & FDCAN_TXFQS_TFQF) != 0U)
    {
      /* Update error code */
      hfdcan->ErrorCode |= HAL_FDCAN_ERROR_FIFO_FULL;

      return HAL_ERROR;
    }

    else
    {
      /* Retrieve the Tx FIFO PutIndex */
      PutIndex = ((hfdcan->Instance->TXFQS & FDCAN_TXFQS_TFQPI) >> FDCAN_TXFQS_TFQPI_Pos);

      // 检查 PutIndex 对应的 Buffer 是否空闲
      if (hfdcan->Instance->TXBRP & ((uint32_t)1 << PutIndex)) {
        // Buffer 正在发送，不能覆盖
        return HAL_ERROR;
      }

      uint8_t *pTxData = NULL;
      if(hfdcan == &hfdcan1) {
        pTxData = uart5RxData;
      }
      else if(hfdcan == &hfdcan2) {
        pTxData = uart4RxData;
      }

      // /* Add the message to the Tx FIFO/Queue */
      // FDCAN_CopyMessageToRAM(hfdcan, pTxHeader, pTxData, PutIndex);
      uint8_t mov_cycle = (8+frame_len)/4+((8+frame_len)%4?1:0);
      for(uint8_t i = 0; i < mov_cycle; i++) {
        *((uint32_t *)(hfdcan->msgRam.TxFIFOQSA+PutIndex*SRAMCAN_TFQ_SIZE)+i) = *(uint32_t *)(&(pTxData[(can_frame_pos + i*4) % BUFFER_SIZE]));
      }

      /* Activate the corresponding transmission request */
      hfdcan->Instance->TXBAR = ((uint32_t)1 << PutIndex);//可以同时发送多个

      /* Store the Latest Tx FIFO/Queue Request Buffer Index */
      hfdcan->LatestTxFifoQRequest = ((uint32_t)1 << PutIndex);
    }

    /* Return function status */
    return HAL_OK;
  }
  else
  {
    /* Update error code */
    hfdcan->ErrorCode |= HAL_FDCAN_ERROR_NOT_STARTED;

    return HAL_ERROR;
  }
}
/* USER CODE END 4 */

void Error_Handler(void)
{
  __disable_irq();
  while (1)
  {
  }
}
